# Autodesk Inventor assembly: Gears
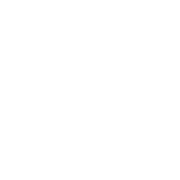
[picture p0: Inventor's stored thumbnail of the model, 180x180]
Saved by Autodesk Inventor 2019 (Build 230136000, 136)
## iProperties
Created: 2019-01
Part Number: Gears
Document SubType Name: Assembly
Designer: m.vorobev
Author: m.vorobev
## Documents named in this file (1)
- C:\Users\m.vorobev.TRINITY\Documents\Inventor\00-000.06.21.21.00\Gears.iam
